# OpenTallas memory compiler (tools/mem_compiler), ASAP7 abstract view, track-aligned v2 (build_aligned_v2.py)
VERSION 5.7 ;
BUSBITCHARS "[]" ;
DIVIDERCHAR "/" ;
PROPERTYDEFINITIONS
  MACRO width INTEGER ;
  MACRO depth INTEGER ;
  MACRO banks INTEGER ;
END PROPERTYDEFINITIONS
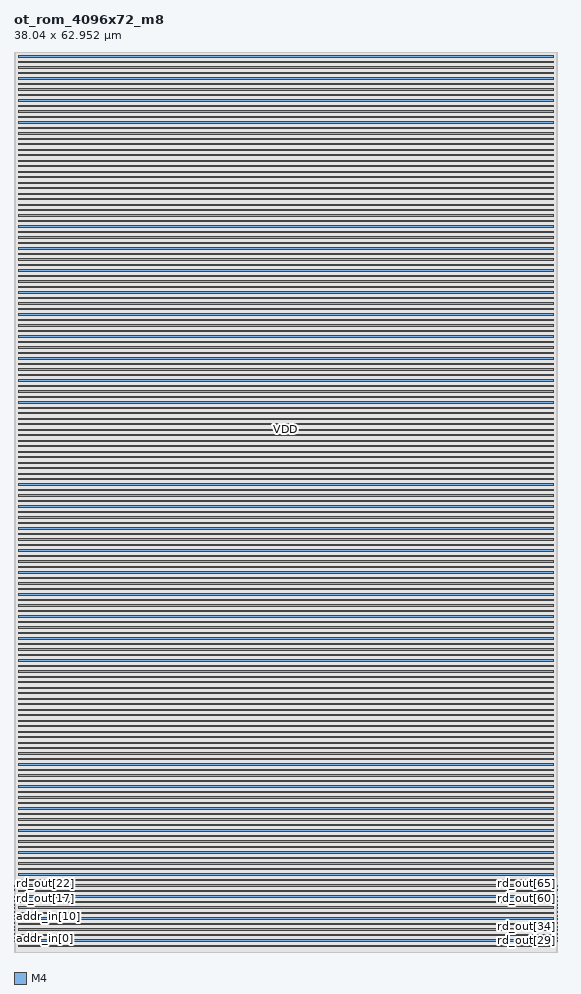
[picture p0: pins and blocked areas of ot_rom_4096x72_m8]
MACRO ot_rom_4096x72_m8
  PROPERTY width 72 ;
  PROPERTY depth 4096 ;
  PROPERTY banks 1 ;
  FOREIGN ot_rom_4096x72_m8 0 0 ;
  SYMMETRY X Y ;
  SIZE 38.040 BY 62.952 ;
  CLASS BLOCK ;
  PIN clk
    DIRECTION INPUT ;
    USE CLOCK ;
    SHAPE ABUTMENT ;
    PORT
      LAYER M4 ;
      RECT 0.000 0.768 0.024 0.792 ;
    END
  END clk
  PIN ce_in
    DIRECTION INPUT ;
    USE SIGNAL ;
    SHAPE ABUTMENT ;
    PORT
      LAYER M4 ;
      RECT 0.000 0.864 0.024 0.888 ;
    END
  END ce_in
  PIN addr_in[0]
    DIRECTION INPUT ;
    USE SIGNAL ;
    SHAPE ABUTMENT ;
    PORT
      LAYER M4 ;
      RECT 0.000 0.960 0.024 0.984 ;
    END
  END addr_in[0]
  PIN addr_in[1]
    DIRECTION INPUT ;
    USE SIGNAL ;
    SHAPE ABUTMENT ;
    PORT
      LAYER M4 ;
      RECT 0.000 1.056 0.024 1.080 ;
    END
  END addr_in[1]
  PIN addr_in[2]
    DIRECTION INPUT ;
    USE SIGNAL ;
    SHAPE ABUTMENT ;
    PORT
      LAYER M4 ;
      RECT 0.000 1.152 0.024 1.176 ;
    END
  END addr_in[2]
  PIN addr_in[3]
    DIRECTION INPUT ;
    USE SIGNAL ;
    SHAPE ABUTMENT ;
    PORT
      LAYER M4 ;
      RECT 0.000 1.248 0.024 1.272 ;
    END
  END addr_in[3]
  PIN addr_in[4]
    DIRECTION INPUT ;
    USE SIGNAL ;
    SHAPE ABUTMENT ;
    PORT
      LAYER M4 ;
      RECT 0.000 1.344 0.024 1.368 ;
    END
  END addr_in[4]
  PIN addr_in[5]
    DIRECTION INPUT ;
    USE SIGNAL ;
    SHAPE ABUTMENT ;
    PORT
      LAYER M4 ;
      RECT 0.000 1.440 0.024 1.464 ;
    END
  END addr_in[5]
  PIN addr_in[6]
    DIRECTION INPUT ;
    USE SIGNAL ;
    SHAPE ABUTMENT ;
    PORT
      LAYER M4 ;
      RECT 0.000 1.536 0.024 1.560 ;
    END
  END addr_in[6]
  PIN addr_in[7]
    DIRECTION INPUT ;
    USE SIGNAL ;
    SHAPE ABUTMENT ;
    PORT
      LAYER M4 ;
      RECT 0.000 1.632 0.024 1.656 ;
    END
  END addr_in[7]
  PIN addr_in[8]
    DIRECTION INPUT ;
    USE SIGNAL ;
    SHAPE ABUTMENT ;
    PORT
      LAYER M4 ;
      RECT 0.000 1.728 0.024 1.752 ;
    END
  END addr_in[8]
  PIN addr_in[9]
    DIRECTION INPUT ;
    USE SIGNAL ;
    SHAPE ABUTMENT ;
    PORT
      LAYER M4 ;
      RECT 0.000 1.824 0.024 1.848 ;
    END
  END addr_in[9]
  PIN addr_in[10]
    DIRECTION INPUT ;
    USE SIGNAL ;
    SHAPE ABUTMENT ;
    PORT
      LAYER M4 ;
      RECT 0.000 1.920 0.024 1.944 ;
    END
  END addr_in[10]
  PIN addr_in[11]
    DIRECTION INPUT ;
    USE SIGNAL ;
    SHAPE ABUTMENT ;
    PORT
      LAYER M4 ;
      RECT 0.000 2.016 0.024 2.040 ;
    END
  END addr_in[11]
  PIN rd_out[0]
    DIRECTION OUTPUT ;
    USE SIGNAL ;
    SHAPE ABUTMENT ;
    PORT
      LAYER M4 ;
      RECT 0.000 2.112 0.024 2.136 ;
    END
  END rd_out[0]
  PIN rd_out[1]
    DIRECTION OUTPUT ;
    USE SIGNAL ;
    SHAPE ABUTMENT ;
    PORT
      LAYER M4 ;
      RECT 0.000 2.208 0.024 2.232 ;
    END
  END rd_out[1]
  PIN rd_out[2]
    DIRECTION OUTPUT ;
    USE SIGNAL ;
    SHAPE ABUTMENT ;
    PORT
      LAYER M4 ;
      RECT 0.000 2.304 0.024 2.328 ;
    END
  END rd_out[2]
  PIN rd_out[3]
    DIRECTION OUTPUT ;
    USE SIGNAL ;
    SHAPE ABUTMENT ;
    PORT
      LAYER M4 ;
      RECT 0.000 2.400 0.024 2.424 ;
    END
  END rd_out[3]
  PIN rd_out[4]
    DIRECTION OUTPUT ;
    USE SIGNAL ;
    SHAPE ABUTMENT ;
    PORT
      LAYER M4 ;
      RECT 0.000 2.496 0.024 2.520 ;
    END
  END rd_out[4]
  PIN rd_out[5]
    DIRECTION OUTPUT ;
    USE SIGNAL ;
    SHAPE ABUTMENT ;
    PORT
      LAYER M4 ;
      RECT 0.000 2.592 0.024 2.616 ;
    END
  END rd_out[5]
  PIN rd_out[6]
    DIRECTION OUTPUT ;
    USE SIGNAL ;
    SHAPE ABUTMENT ;
    PORT
      LAYER M4 ;
      RECT 0.000 2.688 0.024 2.712 ;
    END
  END rd_out[6]
  PIN rd_out[7]
    DIRECTION OUTPUT ;
    USE SIGNAL ;
    SHAPE ABUTMENT ;
    PORT
      LAYER M4 ;
      RECT 0.000 2.784 0.024 2.808 ;
    END
  END rd_out[7]
  PIN rd_out[8]
    DIRECTION OUTPUT ;
    USE SIGNAL ;
    SHAPE ABUTMENT ;
    PORT
      LAYER M4 ;
      RECT 0.000 2.880 0.024 2.904 ;
    END
  END rd_out[8]
  PIN rd_out[9]
    DIRECTION OUTPUT ;
    USE SIGNAL ;
    SHAPE ABUTMENT ;
    PORT
      LAYER M4 ;
      RECT 0.000 2.976 0.024 3.000 ;
    END
  END rd_out[9]
  PIN rd_out[10]
    DIRECTION OUTPUT ;
    USE SIGNAL ;
    SHAPE ABUTMENT ;
    PORT
      LAYER M4 ;
      RECT 0.000 3.072 0.024 3.096 ;
    END
  END rd_out[10]
  PIN rd_out[11]
    DIRECTION OUTPUT ;
    USE SIGNAL ;
    SHAPE ABUTMENT ;
    PORT
      LAYER M4 ;
      RECT 0.000 3.168 0.024 3.192 ;
    END
  END rd_out[11]
  PIN rd_out[12]
    DIRECTION OUTPUT ;
    USE SIGNAL ;
    SHAPE ABUTMENT ;
    PORT
      LAYER M4 ;
      RECT 0.000 3.264 0.024 3.288 ;
    END
  END rd_out[12]
  PIN rd_out[13]
    DIRECTION OUTPUT ;
    USE SIGNAL ;
    SHAPE ABUTMENT ;
    PORT
      LAYER M4 ;
      RECT 0.000 3.360 0.024 3.384 ;
    END
  END rd_out[13]
  PIN rd_out[14]
    DIRECTION OUTPUT ;
    USE SIGNAL ;
    SHAPE ABUTMENT ;
    PORT
      LAYER M4 ;
      RECT 0.000 3.456 0.024 3.480 ;
    END
  END rd_out[14]
  PIN rd_out[15]
    DIRECTION OUTPUT ;
    USE SIGNAL ;
    SHAPE ABUTMENT ;
    PORT
      LAYER M4 ;
      RECT 0.000 3.552 0.024 3.576 ;
    END
  END rd_out[15]
  PIN rd_out[16]
    DIRECTION OUTPUT ;
    USE SIGNAL ;
    SHAPE ABUTMENT ;
    PORT
      LAYER M4 ;
      RECT 0.000 3.648 0.024 3.672 ;
    END
  END rd_out[16]
  PIN rd_out[17]
    DIRECTION OUTPUT ;
    USE SIGNAL ;
    SHAPE ABUTMENT ;
    PORT
      LAYER M4 ;
      RECT 0.000 3.744 0.024 3.768 ;
    END
  END rd_out[17]
  PIN rd_out[18]
    DIRECTION OUTPUT ;
    USE SIGNAL ;
    SHAPE ABUTMENT ;
    PORT
      LAYER M4 ;
      RECT 0.000 3.840 0.024 3.864 ;
    END
  END rd_out[18]
  PIN rd_out[19]
    DIRECTION OUTPUT ;
    USE SIGNAL ;
    SHAPE ABUTMENT ;
    PORT
      LAYER M4 ;
      RECT 0.000 3.936 0.024 3.960 ;
    END
  END rd_out[19]
  PIN rd_out[20]
    DIRECTION OUTPUT ;
    USE SIGNAL ;
    SHAPE ABUTMENT ;
    PORT
      LAYER M4 ;
      RECT 0.000 4.032 0.024 4.056 ;
    END
  END rd_out[20]
  PIN rd_out[21]
    DIRECTION OUTPUT ;
    USE SIGNAL ;
    SHAPE ABUTMENT ;
    PORT
      LAYER M4 ;
      RECT 0.000 4.128 0.024 4.152 ;
    END
  END rd_out[21]
  PIN rd_out[22]
    DIRECTION OUTPUT ;
    USE SIGNAL ;
    SHAPE ABUTMENT ;
    PORT
      LAYER M4 ;
      RECT 0.000 4.224 0.024 4.248 ;
    END
  END rd_out[22]
  PIN rd_out[23]
    DIRECTION OUTPUT ;
    USE SIGNAL ;
    SHAPE ABUTMENT ;
    PORT
      LAYER M4 ;
      RECT 0.000 4.320 0.024 4.344 ;
    END
  END rd_out[23]
  PIN rd_out[24]
    DIRECTION OUTPUT ;
    USE SIGNAL ;
    SHAPE ABUTMENT ;
    PORT
      LAYER M4 ;
      RECT 0.000 4.416 0.024 4.440 ;
    END
  END rd_out[24]
  PIN rd_out[25]
    DIRECTION OUTPUT ;
    USE SIGNAL ;
    SHAPE ABUTMENT ;
    PORT
      LAYER M4 ;
      RECT 0.000 4.512 0.024 4.536 ;
    END
  END rd_out[25]
  PIN rd_out[26]
    DIRECTION OUTPUT ;
    USE SIGNAL ;
    SHAPE ABUTMENT ;
    PORT
      LAYER M4 ;
      RECT 0.000 4.608 0.024 4.632 ;
    END
  END rd_out[26]
  PIN rd_out[27]
    DIRECTION OUTPUT ;
    USE SIGNAL ;
    SHAPE ABUTMENT ;
    PORT
      LAYER M4 ;
      RECT 0.000 4.704 0.024 4.728 ;
    END
  END rd_out[27]
  PIN rd_out[28]
    DIRECTION OUTPUT ;
    USE SIGNAL ;
    SHAPE ABUTMENT ;
    PORT
      LAYER M4 ;
      RECT 0.000 4.800 0.024 4.824 ;
    END
  END rd_out[28]
  PIN rd_out[29]
    DIRECTION OUTPUT ;
    USE SIGNAL ;
    SHAPE ABUTMENT ;
    PORT
      LAYER M4 ;
      RECT 38.016 0.768 38.040 0.792 ;
    END
  END rd_out[29]
  PIN rd_out[30]
    DIRECTION OUTPUT ;
    USE SIGNAL ;
    SHAPE ABUTMENT ;
    PORT
      LAYER M4 ;
      RECT 38.016 0.864 38.040 0.888 ;
    END
  END rd_out[30]
  PIN rd_out[31]
    DIRECTION OUTPUT ;
    USE SIGNAL ;
    SHAPE ABUTMENT ;
    PORT
      LAYER M4 ;
      RECT 38.016 0.960 38.040 0.984 ;
    END
  END rd_out[31]
  PIN rd_out[32]
    DIRECTION OUTPUT ;
    USE SIGNAL ;
    SHAPE ABUTMENT ;
    PORT
      LAYER M4 ;
      RECT 38.016 1.056 38.040 1.080 ;
    END
  END rd_out[32]
  PIN rd_out[33]
    DIRECTION OUTPUT ;
    USE SIGNAL ;
    SHAPE ABUTMENT ;
    PORT
      LAYER M4 ;
      RECT 38.016 1.152 38.040 1.176 ;
    END
  END rd_out[33]
  PIN rd_out[34]
    DIRECTION OUTPUT ;
    USE SIGNAL ;
    SHAPE ABUTMENT ;
    PORT
      LAYER M4 ;
      RECT 38.016 1.248 38.040 1.272 ;
    END
  END rd_out[34]
  PIN rd_out[35]
    DIRECTION OUTPUT ;
    USE SIGNAL ;
    SHAPE ABUTMENT ;
    PORT
      LAYER M4 ;
      RECT 38.016 1.344 38.040 1.368 ;
    END
  END rd_out[35]
  PIN rd_out[36]
    DIRECTION OUTPUT ;
    USE SIGNAL ;
    SHAPE ABUTMENT ;
    PORT
      LAYER M4 ;
      RECT 38.016 1.440 38.040 1.464 ;
    END
  END rd_out[36]
  PIN rd_out[37]
    DIRECTION OUTPUT ;
    USE SIGNAL ;
    SHAPE ABUTMENT ;
    PORT
      LAYER M4 ;
      RECT 38.016 1.536 38.040 1.560 ;
    END
  END rd_out[37]
  PIN rd_out[38]
    DIRECTION OUTPUT ;
    USE SIGNAL ;
    SHAPE ABUTMENT ;
    PORT
      LAYER M4 ;
      RECT 38.016 1.632 38.040 1.656 ;
    END
  END rd_out[38]
  PIN rd_out[39]
    DIRECTION OUTPUT ;
    USE SIGNAL ;
    SHAPE ABUTMENT ;
    PORT
      LAYER M4 ;
      RECT 38.016 1.728 38.040 1.752 ;
    END
  END rd_out[39]
  PIN rd_out[40]
    DIRECTION OUTPUT ;
    USE SIGNAL ;
    SHAPE ABUTMENT ;
    PORT
      LAYER M4 ;
      RECT 38.016 1.824 38.040 1.848 ;
    END
  END rd_out[40]
  PIN rd_out[41]
    DIRECTION OUTPUT ;
    USE SIGNAL ;
    SHAPE ABUTMENT ;
    PORT
      LAYER M4 ;
      RECT 38.016 1.920 38.040 1.944 ;
    END
  END rd_out[41]
  PIN rd_out[42]
    DIRECTION OUTPUT ;
    USE SIGNAL ;
    SHAPE ABUTMENT ;
    PORT
      LAYER M4 ;
      RECT 38.016 2.016 38.040 2.040 ;
    END
  END rd_out[42]
  PIN rd_out[43]
    DIRECTION OUTPUT ;
    USE SIGNAL ;
    SHAPE ABUTMENT ;
    PORT
      LAYER M4 ;
      RECT 38.016 2.112 38.040 2.136 ;
    END
  END rd_out[43]
  PIN rd_out[44]
    DIRECTION OUTPUT ;
    USE SIGNAL ;
    SHAPE ABUTMENT ;
    PORT
      LAYER M4 ;
      RECT 38.016 2.208 38.040 2.232 ;
    END
  END rd_out[44]
  PIN rd_out[45]
    DIRECTION OUTPUT ;
    USE SIGNAL ;
    SHAPE ABUTMENT ;
    PORT
      LAYER M4 ;
      RECT 38.016 2.304 38.040 2.328 ;
    END
  END rd_out[45]
  PIN rd_out[46]
    DIRECTION OUTPUT ;
    USE SIGNAL ;
    SHAPE ABUTMENT ;
    PORT
      LAYER M4 ;
      RECT 38.016 2.400 38.040 2.424 ;
    END
  END rd_out[46]
  PIN rd_out[47]
    DIRECTION OUTPUT ;
    USE SIGNAL ;
    SHAPE ABUTMENT ;
    PORT
      LAYER M4 ;
      RECT 38.016 2.496 38.040 2.520 ;
    END
  END rd_out[47]
  PIN rd_out[48]
    DIRECTION OUTPUT ;
    USE SIGNAL ;
    SHAPE ABUTMENT ;
    PORT
      LAYER M4 ;
      RECT 38.016 2.592 38.040 2.616 ;
    END
  END rd_out[48]
  PIN rd_out[49]
    DIRECTION OUTPUT ;
    USE SIGNAL ;
    SHAPE ABUTMENT ;
    PORT
      LAYER M4 ;
      RECT 38.016 2.688 38.040 2.712 ;
    END
  END rd_out[49]
  PIN rd_out[50]
    DIRECTION OUTPUT ;
    USE SIGNAL ;
    SHAPE ABUTMENT ;
    PORT
      LAYER M4 ;
      RECT 38.016 2.784 38.040 2.808 ;
    END
  END rd_out[50]
  PIN rd_out[51]
    DIRECTION OUTPUT ;
    USE SIGNAL ;
    SHAPE ABUTMENT ;
    PORT
      LAYER M4 ;
      RECT 38.016 2.880 38.040 2.904 ;
    END
  END rd_out[51]
  PIN rd_out[52]
    DIRECTION OUTPUT ;
    USE SIGNAL ;
    SHAPE ABUTMENT ;
    PORT
      LAYER M4 ;
      RECT 38.016 2.976 38.040 3.000 ;
    END
  END rd_out[52]
  PIN rd_out[53]
    DIRECTION OUTPUT ;
    USE SIGNAL ;
    SHAPE ABUTMENT ;
    PORT
      LAYER M4 ;
      RECT 38.016 3.072 38.040 3.096 ;
    END
  END rd_out[53]
  PIN rd_out[54]
    DIRECTION OUTPUT ;
    USE SIGNAL ;
    SHAPE ABUTMENT ;
    PORT
      LAYER M4 ;
      RECT 38.016 3.168 38.040 3.192 ;
    END
  END rd_out[54]
  PIN rd_out[55]
    DIRECTION OUTPUT ;
    USE SIGNAL ;
    SHAPE ABUTMENT ;
    PORT
      LAYER M4 ;
      RECT 38.016 3.264 38.040 3.288 ;
    END
  END rd_out[55]
  PIN rd_out[56]
    DIRECTION OUTPUT ;
    USE SIGNAL ;
    SHAPE ABUTMENT ;
    PORT
      LAYER M4 ;
      RECT 38.016 3.360 38.040 3.384 ;
    END
  END rd_out[56]
  PIN rd_out[57]
    DIRECTION OUTPUT ;
    USE SIGNAL ;
    SHAPE ABUTMENT ;
    PORT
      LAYER M4 ;
      RECT 38.016 3.456 38.040 3.480 ;
    END
  END rd_out[57]
  PIN rd_out[58]
    DIRECTION OUTPUT ;
    USE SIGNAL ;
    SHAPE ABUTMENT ;
    PORT
      LAYER M4 ;
      RECT 38.016 3.552 38.040 3.576 ;
    END
  END rd_out[58]
  PIN rd_out[59]
    DIRECTION OUTPUT ;
    USE SIGNAL ;
    SHAPE ABUTMENT ;
    PORT
      LAYER M4 ;
      RECT 38.016 3.648 38.040 3.672 ;
    END
  END rd_out[59]
  PIN rd_out[60]
    DIRECTION OUTPUT ;
    USE SIGNAL ;
    SHAPE ABUTMENT ;
    PORT
      LAYER M4 ;
      RECT 38.016 3.744 38.040 3.768 ;
    END
  END rd_out[60]
  PIN rd_out[61]
    DIRECTION OUTPUT ;
    USE SIGNAL ;
    SHAPE ABUTMENT ;
    PORT
      LAYER M4 ;
      RECT 38.016 3.840 38.040 3.864 ;
    END
  END rd_out[61]
  PIN rd_out[62]
    DIRECTION OUTPUT ;
    USE SIGNAL ;
    SHAPE ABUTMENT ;
    PORT
      LAYER M4 ;
      RECT 38.016 3.936 38.040 3.960 ;
    END
  END rd_out[62]
  PIN rd_out[63]
    DIRECTION OUTPUT ;
    USE SIGNAL ;
    SHAPE ABUTMENT ;
    PORT
      LAYER M4 ;
      RECT 38.016 4.032 38.040 4.056 ;
    END
  END rd_out[63]
  PIN rd_out[64]
    DIRECTION OUTPUT ;
    USE SIGNAL ;
    SHAPE ABUTMENT ;
    PORT
      LAYER M4 ;
      RECT 38.016 4.128 38.040 4.152 ;
    END
  END rd_out[64]
  PIN rd_out[65]
    DIRECTION OUTPUT ;
    USE SIGNAL ;
    SHAPE ABUTMENT ;
    PORT
      LAYER M4 ;
      RECT 38.016 4.224 38.040 4.248 ;
    END
  END rd_out[65]
  PIN rd_out[66]
    DIRECTION OUTPUT ;
    USE SIGNAL ;
    SHAPE ABUTMENT ;
    PORT
      LAYER M4 ;
      RECT 38.016 4.320 38.040 4.344 ;
    END
  END rd_out[66]
  PIN rd_out[67]
    DIRECTION OUTPUT ;
    USE SIGNAL ;
    SHAPE ABUTMENT ;
    PORT
      LAYER M4 ;
      RECT 38.016 4.416 38.040 4.440 ;
    END
  END rd_out[67]
  PIN rd_out[68]
    DIRECTION OUTPUT ;
    USE SIGNAL ;
    SHAPE ABUTMENT ;
    PORT
      LAYER M4 ;
      RECT 38.016 4.512 38.040 4.536 ;
    END
  END rd_out[68]
  PIN rd_out[69]
    DIRECTION OUTPUT ;
    USE SIGNAL ;
    SHAPE ABUTMENT ;
    PORT
      LAYER M4 ;
      RECT 38.016 4.608 38.040 4.632 ;
    END
  END rd_out[69]
  PIN rd_out[70]
    DIRECTION OUTPUT ;
    USE SIGNAL ;
    SHAPE ABUTMENT ;
    PORT
      LAYER M4 ;
      RECT 38.016 4.704 38.040 4.728 ;
    END
  END rd_out[70]
  PIN rd_out[71]
    DIRECTION OUTPUT ;
    USE SIGNAL ;
    SHAPE ABUTMENT ;
    PORT
      LAYER M4 ;
      RECT 38.016 4.800 38.040 4.824 ;
    END
  END rd_out[71]
  PIN VDD
    DIRECTION INOUT ;
    USE POWER ;
    PORT
      LAYER M4 ;
      RECT 0.300 0.384 37.740 0.480 ;
      RECT 0.300 1.152 37.740 1.248 ;
      RECT 0.300 1.920 37.740 2.016 ;
      RECT 0.300 2.688 37.740 2.784 ;
      RECT 0.300 3.456 37.740 3.552 ;
      RECT 0.300 4.224 37.740 4.320 ;
      RECT 0.300 4.992 37.740 5.088 ;
      RECT 0.300 5.760 37.740 5.856 ;
      RECT 0.300 6.528 37.740 6.624 ;
      RECT 0.300 7.296 37.740 7.392 ;
      RECT 0.300 8.064 37.740 8.160 ;
      RECT 0.300 8.832 37.740 8.928 ;
      RECT 0.300 9.600 37.740 9.696 ;
      RECT 0.300 10.368 37.740 10.464 ;
      RECT 0.300 11.136 37.740 11.232 ;
      RECT 0.300 11.904 37.740 12.000 ;
      RECT 0.300 12.672 37.740 12.768 ;
      RECT 0.300 13.440 37.740 13.536 ;
      RECT 0.300 14.208 37.740 14.304 ;
      RECT 0.300 14.976 37.740 15.072 ;
      RECT 0.300 15.744 37.740 15.840 ;
      RECT 0.300 16.512 37.740 16.608 ;
      RECT 0.300 17.280 37.740 17.376 ;
      RECT 0.300 18.048 37.740 18.144 ;
      RECT 0.300 18.816 37.740 18.912 ;
      RECT 0.300 19.584 37.740 19.680 ;
      RECT 0.300 20.352 37.740 20.448 ;
      RECT 0.300 21.120 37.740 21.216 ;
      RECT 0.300 21.888 37.740 21.984 ;
      RECT 0.300 22.656 37.740 22.752 ;
      RECT 0.300 23.424 37.740 23.520 ;
      RECT 0.300 24.192 37.740 24.288 ;
      RECT 0.300 24.960 37.740 25.056 ;
      RECT 0.300 25.728 37.740 25.824 ;
      RECT 0.300 26.496 37.740 26.592 ;
      RECT 0.300 27.264 37.740 27.360 ;
      RECT 0.300 28.032 37.740 28.128 ;
      RECT 0.300 28.800 37.740 28.896 ;
      RECT 0.300 29.568 37.740 29.664 ;
      RECT 0.300 30.336 37.740 30.432 ;
      RECT 0.300 31.104 37.740 31.200 ;
      RECT 0.300 31.872 37.740 31.968 ;
      RECT 0.300 32.640 37.740 32.736 ;
      RECT 0.300 33.408 37.740 33.504 ;
      RECT 0.300 34.176 37.740 34.272 ;
      RECT 0.300 34.944 37.740 35.040 ;
      RECT 0.300 35.712 37.740 35.808 ;
      RECT 0.300 36.480 37.740 36.576 ;
      RECT 0.300 37.248 37.740 37.344 ;
      RECT 0.300 38.016 37.740 38.112 ;
      RECT 0.300 38.784 37.740 38.880 ;
      RECT 0.300 39.552 37.740 39.648 ;
      RECT 0.300 40.320 37.740 40.416 ;
      RECT 0.300 41.088 37.740 41.184 ;
      RECT 0.300 41.856 37.740 41.952 ;
      RECT 0.300 42.624 37.740 42.720 ;
      RECT 0.300 43.392 37.740 43.488 ;
      RECT 0.300 44.160 37.740 44.256 ;
      RECT 0.300 44.928 37.740 45.024 ;
      RECT 0.300 45.696 37.740 45.792 ;
      RECT 0.300 46.464 37.740 46.560 ;
      RECT 0.300 47.232 37.740 47.328 ;
      RECT 0.300 48.000 37.740 48.096 ;
      RECT 0.300 48.768 37.740 48.864 ;
      RECT 0.300 49.536 37.740 49.632 ;
      RECT 0.300 50.304 37.740 50.400 ;
      RECT 0.300 51.072 37.740 51.168 ;
      RECT 0.300 51.840 37.740 51.936 ;
      RECT 0.300 52.608 37.740 52.704 ;
      RECT 0.300 53.376 37.740 53.472 ;
      RECT 0.300 54.144 37.740 54.240 ;
      RECT 0.300 54.912 37.740 55.008 ;
      RECT 0.300 55.680 37.740 55.776 ;
      RECT 0.300 56.448 37.740 56.544 ;
      RECT 0.300 57.216 37.740 57.312 ;
      RECT 0.300 57.984 37.740 58.080 ;
      RECT 0.300 58.752 37.740 58.848 ;
      RECT 0.300 59.520 37.740 59.616 ;
      RECT 0.300 60.288 37.740 60.384 ;
      RECT 0.300 61.056 37.740 61.152 ;
      RECT 0.300 61.824 37.740 61.920 ;
      RECT 0.300 62.592 37.740 62.688 ;
    END
  END VDD
  PIN VSS
    DIRECTION INOUT ;
    USE GROUND ;
    PORT
      LAYER M4 ;
      RECT 0.300 0.768 37.740 0.864 ;
      RECT 0.300 1.536 37.740 1.632 ;
      RECT 0.300 2.304 37.740 2.400 ;
      RECT 0.300 3.072 37.740 3.168 ;
      RECT 0.300 3.840 37.740 3.936 ;
      RECT 0.300 4.608 37.740 4.704 ;
      RECT 0.300 5.376 37.740 5.472 ;
      RECT 0.300 6.144 37.740 6.240 ;
      RECT 0.300 6.912 37.740 7.008 ;
      RECT 0.300 7.680 37.740 7.776 ;
      RECT 0.300 8.448 37.740 8.544 ;
      RECT 0.300 9.216 37.740 9.312 ;
      RECT 0.300 9.984 37.740 10.080 ;
      RECT 0.300 10.752 37.740 10.848 ;
      RECT 0.300 11.520 37.740 11.616 ;
      RECT 0.300 12.288 37.740 12.384 ;
      RECT 0.300 13.056 37.740 13.152 ;
      RECT 0.300 13.824 37.740 13.920 ;
      RECT 0.300 14.592 37.740 14.688 ;
      RECT 0.300 15.360 37.740 15.456 ;
      RECT 0.300 16.128 37.740 16.224 ;
      RECT 0.300 16.896 37.740 16.992 ;
      RECT 0.300 17.664 37.740 17.760 ;
      RECT 0.300 18.432 37.740 18.528 ;
      RECT 0.300 19.200 37.740 19.296 ;
      RECT 0.300 19.968 37.740 20.064 ;
      RECT 0.300 20.736 37.740 20.832 ;
      RECT 0.300 21.504 37.740 21.600 ;
      RECT 0.300 22.272 37.740 22.368 ;
      RECT 0.300 23.040 37.740 23.136 ;
      RECT 0.300 23.808 37.740 23.904 ;
      RECT 0.300 24.576 37.740 24.672 ;
      RECT 0.300 25.344 37.740 25.440 ;
      RECT 0.300 26.112 37.740 26.208 ;
      RECT 0.300 26.880 37.740 26.976 ;
      RECT 0.300 27.648 37.740 27.744 ;
      RECT 0.300 28.416 37.740 28.512 ;
      RECT 0.300 29.184 37.740 29.280 ;
      RECT 0.300 29.952 37.740 30.048 ;
      RECT 0.300 30.720 37.740 30.816 ;
      RECT 0.300 31.488 37.740 31.584 ;
      RECT 0.300 32.256 37.740 32.352 ;
      RECT 0.300 33.024 37.740 33.120 ;
      RECT 0.300 33.792 37.740 33.888 ;
      RECT 0.300 34.560 37.740 34.656 ;
      RECT 0.300 35.328 37.740 35.424 ;
      RECT 0.300 36.096 37.740 36.192 ;
      RECT 0.300 36.864 37.740 36.960 ;
      RECT 0.300 37.632 37.740 37.728 ;
      RECT 0.300 38.400 37.740 38.496 ;
      RECT 0.300 39.168 37.740 39.264 ;
      RECT 0.300 39.936 37.740 40.032 ;
      RECT 0.300 40.704 37.740 40.800 ;
      RECT 0.300 41.472 37.740 41.568 ;
      RECT 0.300 42.240 37.740 42.336 ;
      RECT 0.300 43.008 37.740 43.104 ;
      RECT 0.300 43.776 37.740 43.872 ;
      RECT 0.300 44.544 37.740 44.640 ;
      RECT 0.300 45.312 37.740 45.408 ;
      RECT 0.300 46.080 37.740 46.176 ;
      RECT 0.300 46.848 37.740 46.944 ;
      RECT 0.300 47.616 37.740 47.712 ;
      RECT 0.300 48.384 37.740 48.480 ;
      RECT 0.300 49.152 37.740 49.248 ;
      RECT 0.300 49.920 37.740 50.016 ;
      RECT 0.300 50.688 37.740 50.784 ;
      RECT 0.300 51.456 37.740 51.552 ;
      RECT 0.300 52.224 37.740 52.320 ;
      RECT 0.300 52.992 37.740 53.088 ;
      RECT 0.300 53.760 37.740 53.856 ;
      RECT 0.300 54.528 37.740 54.624 ;
      RECT 0.300 55.296 37.740 55.392 ;
      RECT 0.300 56.064 37.740 56.160 ;
      RECT 0.300 56.832 37.740 56.928 ;
      RECT 0.300 57.600 37.740 57.696 ;
      RECT 0.300 58.368 37.740 58.464 ;
      RECT 0.300 59.136 37.740 59.232 ;
      RECT 0.300 59.904 37.740 60.000 ;
      RECT 0.300 60.672 37.740 60.768 ;
      RECT 0.300 61.440 37.740 61.536 ;
      RECT 0.300 62.208 37.740 62.304 ;
    END
  END VSS
  OBS
    LAYER M1 ;
    RECT 0 0 38.040 62.952 ;
    LAYER M2 ;
    RECT 0 0 38.040 62.952 ;
    LAYER M3 ;
    RECT 0 0 38.040 62.952 ;
    LAYER M4 ;
    RECT 0.072 0 37.968 62.952 ;
  END
END ot_rom_4096x72_m8

END LIBRARY
